VERSION 5.7 ;
  NOWIREEXTENSIONATPIN ON ;
  DIVIDERCHAR "/" ;
  BUSBITCHARS "[]" ;
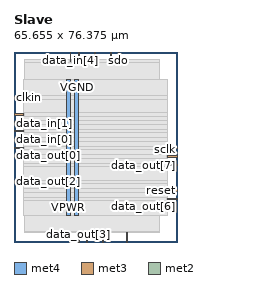
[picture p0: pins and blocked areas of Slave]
MACRO Slave
  CLASS BLOCK ;
  FOREIGN Slave ;
  ORIGIN 0.000 0.000 ;
  SIZE 65.655 BY 76.375 ;
  PIN VGND
    DIRECTION INOUT ;
    USE GROUND ;
    PORT
      LAYER met4 ;
        RECT 24.340 10.640 25.940 65.520 ;
    END
  END VGND
  PIN VPWR
    DIRECTION INOUT ;
    USE POWER ;
    PORT
      LAYER met4 ;
        RECT 21.040 10.640 22.640 65.520 ;
    END
  END VPWR
  PIN clkin
    DIRECTION INPUT ;
    USE SIGNAL ;
    ANTENNAGATEAREA 0.852000 ;
    PORT
      LAYER met3 ;
        RECT 0.000 57.840 4.000 58.440 ;
    END
  END clkin
  PIN data_in[0]
    DIRECTION INPUT ;
    USE SIGNAL ;
    ANTENNAGATEAREA 0.196500 ;
    PORT
      LAYER met3 ;
        RECT 0.000 40.840 4.000 41.440 ;
    END
  END data_in[0]
  PIN data_in[1]
    DIRECTION INPUT ;
    USE SIGNAL ;
    ANTENNAGATEAREA 0.196500 ;
    PORT
      LAYER met3 ;
        RECT 0.000 44.240 4.000 44.840 ;
    END
  END data_in[1]
  PIN data_in[2]
    DIRECTION INPUT ;
    USE SIGNAL ;
    ANTENNAGATEAREA 0.196500 ;
    PORT
      LAYER met3 ;
        RECT 0.000 47.640 4.000 48.240 ;
    END
  END data_in[2]
  PIN data_in[3]
    DIRECTION INPUT ;
    USE SIGNAL ;
    ANTENNAGATEAREA 0.196500 ;
    PORT
      LAYER met3 ;
        RECT 0.000 51.040 4.000 51.640 ;
    END
  END data_in[3]
  PIN data_in[4]
    DIRECTION INPUT ;
    USE SIGNAL ;
    ANTENNAGATEAREA 0.196500 ;
    PORT
      LAYER met2 ;
        RECT 22.630 72.375 22.910 76.375 ;
    END
  END data_in[4]
  PIN data_in[5]
    DIRECTION INPUT ;
    USE SIGNAL ;
    ANTENNAGATEAREA 0.196500 ;
    PORT
      LAYER met2 ;
        RECT 25.850 72.375 26.130 76.375 ;
    END
  END data_in[5]
  PIN data_in[6]
    DIRECTION INPUT ;
    USE SIGNAL ;
    ANTENNAGATEAREA 0.196500 ;
    PORT
      LAYER met2 ;
        RECT 32.290 72.375 32.570 76.375 ;
    END
  END data_in[6]
  PIN data_in[7]
    DIRECTION INPUT ;
    USE SIGNAL ;
    ANTENNAGATEAREA 0.196500 ;
    PORT
      LAYER met2 ;
        RECT 38.730 72.375 39.010 76.375 ;
    END
  END data_in[7]
  PIN data_out[0]
    DIRECTION OUTPUT ;
    USE SIGNAL ;
    ANTENNADIFFAREA 0.445500 ;
    PORT
      LAYER met3 ;
        RECT 0.000 37.440 4.000 38.040 ;
    END
  END data_out[0]
  PIN data_out[1]
    DIRECTION OUTPUT ;
    USE SIGNAL ;
    ANTENNADIFFAREA 0.445500 ;
    PORT
      LAYER met2 ;
        RECT 29.070 0.000 29.350 4.000 ;
    END
  END data_out[1]
  PIN data_out[2]
    DIRECTION OUTPUT ;
    USE SIGNAL ;
    ANTENNADIFFAREA 0.445500 ;
    PORT
      LAYER met3 ;
        RECT 0.000 23.840 4.000 24.440 ;
    END
  END data_out[2]
  PIN data_out[3]
    DIRECTION OUTPUT ;
    USE SIGNAL ;
    ANTENNADIFFAREA 0.445500 ;
    PORT
      LAYER met2 ;
        RECT 25.850 0.000 26.130 4.000 ;
    END
  END data_out[3]
  PIN data_out[4]
    DIRECTION OUTPUT ;
    USE SIGNAL ;
    ANTENNADIFFAREA 0.445500 ;
    PORT
      LAYER met2 ;
        RECT 35.510 0.000 35.790 4.000 ;
    END
  END data_out[4]
  PIN data_out[5]
    DIRECTION OUTPUT ;
    USE SIGNAL ;
    ANTENNADIFFAREA 0.445500 ;
    PORT
      LAYER met2 ;
        RECT 45.170 0.000 45.450 4.000 ;
    END
  END data_out[5]
  PIN data_out[6]
    DIRECTION OUTPUT ;
    USE SIGNAL ;
    ANTENNADIFFAREA 0.445500 ;
    PORT
      LAYER met3 ;
        RECT 61.655 17.040 65.655 17.640 ;
    END
  END data_out[6]
  PIN data_out[7]
    DIRECTION OUTPUT ;
    USE SIGNAL ;
    ANTENNADIFFAREA 0.445500 ;
    PORT
      LAYER met3 ;
        RECT 61.655 30.640 65.655 31.240 ;
    END
  END data_out[7]
  PIN reset
    DIRECTION INPUT ;
    USE SIGNAL ;
    ANTENNAGATEAREA 0.196500 ;
    PORT
      LAYER met3 ;
        RECT 61.655 20.440 65.655 21.040 ;
    END
  END reset
  PIN sclk
    DIRECTION INPUT ;
    USE SIGNAL ;
    ANTENNAGATEAREA 0.196500 ;
    PORT
      LAYER met3 ;
        RECT 61.655 34.040 65.655 34.640 ;
    END
  END sclk
  PIN sdi
    DIRECTION INPUT ;
    USE SIGNAL ;
    ANTENNAGATEAREA 0.196500 ;
    PORT
      LAYER met3 ;
        RECT 0.000 34.040 4.000 34.640 ;
    END
  END sdi
  PIN sdo
    DIRECTION OUTPUT ;
    USE SIGNAL ;
    ANTENNADIFFAREA 0.445500 ;
    PORT
      LAYER met2 ;
        RECT 41.950 72.375 42.230 76.375 ;
    END
  END sdo
  PIN slave_select_in
    DIRECTION INPUT ;
    USE SIGNAL ;
    ANTENNAGATEAREA 0.159000 ;
    PORT
      LAYER met3 ;
        RECT 61.655 37.440 65.655 38.040 ;
    END
  END slave_select_in
  OBS
      LAYER nwell ;
        RECT 5.330 10.795 59.990 65.365 ;
      LAYER li1 ;
        RECT 5.520 10.795 59.800 65.365 ;
      LAYER met1 ;
        RECT 4.210 10.640 59.800 65.520 ;
      LAYER met2 ;
        RECT 4.230 72.095 22.350 73.170 ;
        RECT 23.190 72.095 25.570 73.170 ;
        RECT 26.410 72.095 32.010 73.170 ;
        RECT 32.850 72.095 38.450 73.170 ;
        RECT 39.290 72.095 41.670 73.170 ;
        RECT 42.510 72.095 58.330 73.170 ;
        RECT 4.230 4.280 58.330 72.095 ;
        RECT 4.230 4.000 25.570 4.280 ;
        RECT 26.410 4.000 28.790 4.280 ;
        RECT 29.630 4.000 35.230 4.280 ;
        RECT 36.070 4.000 44.890 4.280 ;
        RECT 45.730 4.000 58.330 4.280 ;
      LAYER met3 ;
        RECT 3.990 58.840 61.655 65.445 ;
        RECT 4.400 57.440 61.655 58.840 ;
        RECT 3.990 52.040 61.655 57.440 ;
        RECT 4.400 50.640 61.655 52.040 ;
        RECT 3.990 48.640 61.655 50.640 ;
        RECT 4.400 47.240 61.655 48.640 ;
        RECT 3.990 45.240 61.655 47.240 ;
        RECT 4.400 43.840 61.655 45.240 ;
        RECT 3.990 41.840 61.655 43.840 ;
        RECT 4.400 40.440 61.655 41.840 ;
        RECT 3.990 38.440 61.655 40.440 ;
        RECT 4.400 37.040 61.255 38.440 ;
        RECT 3.990 35.040 61.655 37.040 ;
        RECT 4.400 33.640 61.255 35.040 ;
        RECT 3.990 31.640 61.655 33.640 ;
        RECT 3.990 30.240 61.255 31.640 ;
        RECT 3.990 24.840 61.655 30.240 ;
        RECT 4.400 23.440 61.655 24.840 ;
        RECT 3.990 21.440 61.655 23.440 ;
        RECT 3.990 20.040 61.255 21.440 ;
        RECT 3.990 18.040 61.655 20.040 ;
        RECT 3.990 16.640 61.255 18.040 ;
        RECT 3.990 10.715 61.655 16.640 ;
  END
END Slave
END LIBRARY

